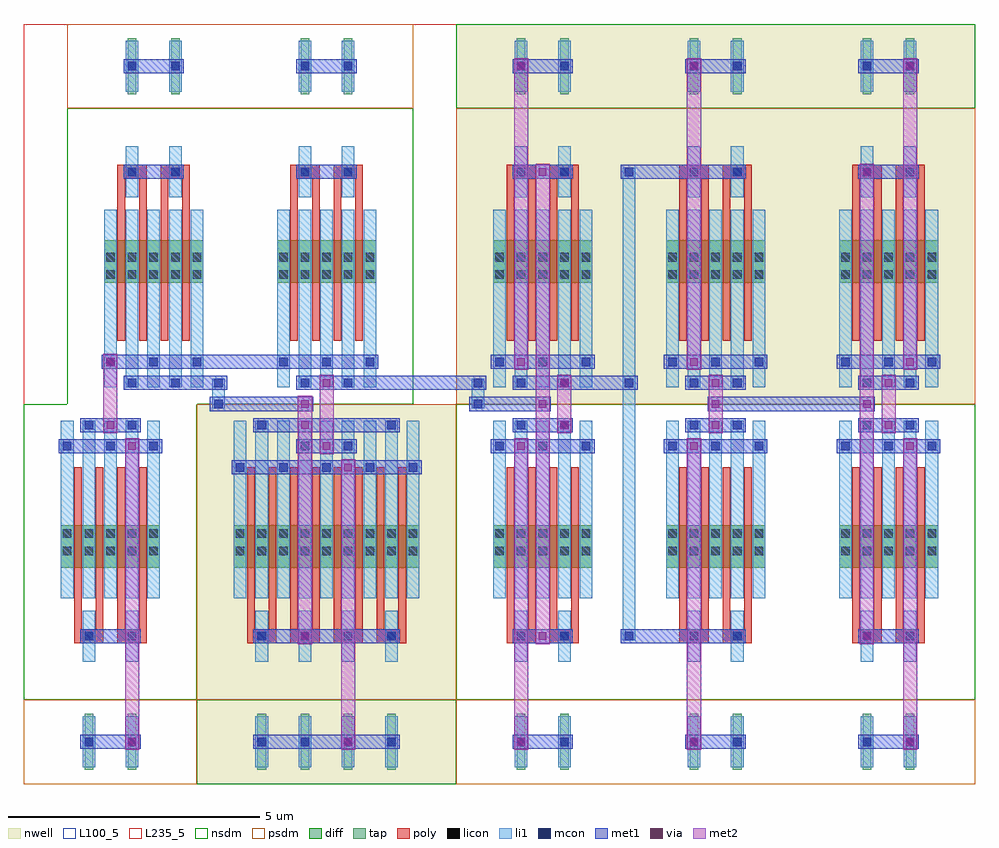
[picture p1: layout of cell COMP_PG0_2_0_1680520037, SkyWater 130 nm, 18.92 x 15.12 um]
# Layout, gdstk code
from math import pi, radians
import gdstk
lib = gdstk.Library(unit=1e-6, precision=1e-09)
def R(c, l, rs):  # rectangles x0, y0, x1, y1
    for r in rs: c.add(gdstk.rectangle(r[:2], r[2:], *l))
def A(c, l, x, y, w, h, nx, ny, dx, dy):  # array of equal rectangles
    R(c, l, [(x+i*dx, y+j*dy, x+i*dx+w, y+j*dy+h) for i in range(nx) for j in range(ny)])
def P(c, l, *ps):  # polygons
    for p in ps: c.add(gdstk.Polygon(p, *l))
nwell = (64, 20)
diff = (65, 20)
tap = (65, 44)
poly = (66, 20)
licon = (66, 44)
li1 = (67, 20)
mcon = (67, 44)
met1 = (68, 20)
via = (68, 44)
met2 = (69, 20)
nsdm = (93, 44)
psdm = (94, 20)
L100_5 = (100, 5)
L235_5 = (235, 5)

nmos_s_74334133_x2_y1_16 = lib.new_cell('NMOS_S_74334133_X2_Y1_1680520030_1680520031_1680520037')
R(nmos_s_74334133_x2_y1_16, diff, [(0.735,2.415,2.705,3.255)])
R(nmos_s_74334133_x2_y1_16, tap, [(1.205,6.16,1.375,7.28), (2.065,6.16,2.235,7.28)])
A(nmos_s_74334133_x2_y1_16, poly, 1, 1.26, 0.15, 3.36, 4, 1, 0.43, 0)
R(nmos_s_74334133_x2_y1_16, poly, [(1,4.485,1.58,4.755), (1.86,4.485,2.44,4.755)])
A(nmos_s_74334133_x2_y1_16, licon, 0.775, 2.495, 0.17, 0.17, 3, 2, 0.43, 0.34)
A(nmos_s_74334133_x2_y1_16, licon, 1.635, 2.495, 0.17, 0.17, 3, 2, 0.43, 0.34)
R(nmos_s_74334133_x2_y1_16, licon, [(1.205,4.535,1.375,4.705), (2.065,4.535,2.235,4.705), (1.205,6.635,1.375,6.805), (2.065,6.635,2.235,6.805)])
A(nmos_s_74334133_x2_y1_16, li1, 0.735, 0.335, 0.25, 3.53, 5, 1, 0.43, 0)
R(nmos_s_74334133_x2_y1_16, li1, [(1.165,4.115,1.415,5.125), (2.025,4.115,2.275,5.125), (1.165,6.215,1.415,7.225), (2.025,6.215,2.275,7.225)])
A(nmos_s_74334133_x2_y1_16, mcon, 0.775, 0.755, 0.17, 0.17, 3, 1, 0.86, 0)
R(nmos_s_74334133_x2_y1_16, mcon, [(1.205,0.335,1.375,0.505), (2.065,0.335,2.235,0.505), (1.205,4.535,1.375,4.705), (2.065,4.535,2.235,4.705), (1.205,6.635,1.375,6.805), (2.065,6.635,2.235,6.805)])
R(nmos_s_74334133_x2_y1_16, met1, [(1.12,0.28,2.32,0.56), (0.69,0.7,2.75,0.98), (1.12,4.48,2.32,4.76), (1.12,6.58,2.32,6.86)])
R(nmos_s_74334133_x2_y1_16, via, [(2.075,0.765,2.225,0.915), (2.075,6.645,2.225,6.795)])
R(nmos_s_74334133_x2_y1_16, met2, [(2.01,0.68,2.29,6.88)])
R(nmos_s_74334133_x2_y1_16, nsdm, [(0,0,3.44,5.88)])
R(nmos_s_74334133_x2_y1_16, psdm, [(0,5.88,3.44,7.56)])
R(nmos_s_74334133_x2_y1_16, L100_5, [(0,0,3.44,7.56)])

pmos_s_33331942_x2_y1_16 = lib.new_cell('PMOS_S_33331942_X2_Y1_1680520031_1680520031_1680520037')
R(pmos_s_33331942_x2_y1_16, nwell, [(0,0,3.44,7.56)])
R(pmos_s_33331942_x2_y1_16, diff, [(0.735,2.415,2.705,3.255)])
R(pmos_s_33331942_x2_y1_16, tap, [(1.205,6.16,1.375,7.28), (2.065,6.16,2.235,7.28)])
A(pmos_s_33331942_x2_y1_16, poly, 1, 1.26, 0.15, 3.36, 4, 1, 0.43, 0)
R(pmos_s_33331942_x2_y1_16, poly, [(1,4.485,1.58,4.755), (1.86,4.485,2.44,4.755)])
A(pmos_s_33331942_x2_y1_16, licon, 0.775, 2.495, 0.17, 0.17, 3, 2, 0.43, 0.34)
A(pmos_s_33331942_x2_y1_16, licon, 1.635, 2.495, 0.17, 0.17, 3, 2, 0.43, 0.34)
R(pmos_s_33331942_x2_y1_16, licon, [(1.205,4.535,1.375,4.705), (2.065,4.535,2.235,4.705), (1.205,6.635,1.375,6.805), (2.065,6.635,2.235,6.805)])
A(pmos_s_33331942_x2_y1_16, li1, 0.735, 0.335, 0.25, 3.53, 5, 1, 0.43, 0)
R(pmos_s_33331942_x2_y1_16, li1, [(1.165,4.115,1.415,5.125), (2.025,4.115,2.275,5.125), (1.165,6.215,1.415,7.225), (2.025,6.215,2.275,7.225)])
A(pmos_s_33331942_x2_y1_16, mcon, 0.775, 0.755, 0.17, 0.17, 3, 1, 0.86, 0)
R(pmos_s_33331942_x2_y1_16, mcon, [(1.205,0.335,1.375,0.505), (2.065,0.335,2.235,0.505), (1.205,4.535,1.375,4.705), (2.065,4.535,2.235,4.705), (1.205,6.635,1.375,6.805), (2.065,6.635,2.235,6.805)])
R(pmos_s_33331942_x2_y1_16, met1, [(1.12,0.28,2.32,0.56), (0.69,0.7,2.75,0.98), (1.12,4.48,2.32,4.76), (1.12,6.58,2.32,6.86)])
R(pmos_s_33331942_x2_y1_16, via, [(2.075,0.765,2.225,0.915), (2.075,6.645,2.225,6.795)])
R(pmos_s_33331942_x2_y1_16, met2, [(2.01,0.68,2.29,6.88)])
R(pmos_s_33331942_x2_y1_16, nsdm, [(0,5.88,3.44,7.56)])
R(pmos_s_33331942_x2_y1_16, psdm, [(0,0,3.44,5.88)])
R(pmos_s_33331942_x2_y1_16, L100_5, [(0,0,3.44,7.56)])

stage2_inv_90501218_pg0_ = lib.new_cell('STAGE2_INV_90501218_PG0_2_0_1680520031_1680520037')
R(stage2_inv_90501218_pg0_, li1, [(3.315,2.855,3.565,3.025), (3.315,2.855,3.565,3.025), (3.315,2.94,3.565,7.98), (3.315,7.895,3.565,8.065), (3.315,7.895,3.565,8.065), (3.315,7.895,3.565,8.065), (3.315,7.895,3.565,8.065), (3.315,7.895,3.565,8.065), (3.315,7.895,3.565,8.065), (3.315,7.98,3.565,12.18), (3.315,12.095,3.565,12.265), (3.315,12.095,3.565,12.265), (3.315,12.095,3.565,12.265), (3.315,12.095,3.565,12.265), (3.315,12.095,3.565,12.265), (3.315,12.095,3.565,12.265)])
R(stage2_inv_90501218_pg0_, mcon, [(3.355,2.855,3.525,3.025), (3.355,2.855,3.525,3.025), (3.355,7.895,3.525,8.065), (3.355,7.895,3.525,8.065), (3.355,7.895,3.525,8.065), (3.355,7.895,3.525,8.065), (3.355,7.895,3.525,8.065), (3.355,7.895,3.525,8.065), (3.355,12.095,3.525,12.265), (3.355,12.095,3.525,12.265), (3.355,12.095,3.525,12.265), (3.355,12.095,3.525,12.265), (3.355,12.095,3.525,12.265), (3.355,12.095,3.525,12.265)])
R(stage2_inv_90501218_pg0_, met1, [(2.15,2.8,3.44,3.08), (3.27,2.8,3.61,3.08), (3.27,2.8,3.61,3.08), (5,2.8,5.32,3.08), (5,2.8,5.32,3.08), (1.56,7,1.88,7.28), (1.56,7,1.88,7.28), (4.57,7,4.89,7.28), (4.57,7,4.89,7.28), (4.57,7,4.89,7.28), (4.57,7,4.89,7.28), (1.56,7.84,1.88,8.12), (1.56,7.84,1.88,8.12), (3.27,7.84,3.61,8.12), (3.27,7.84,3.61,8.12), (3.27,7.84,3.61,8.12), (3.27,7.84,3.61,8.12), (3.27,7.84,3.61,8.12), (3.27,7.84,3.61,8.12), (3.44,7.84,4.73,8.12), (4.57,7.84,4.89,8.12), (4.57,7.84,4.89,8.12), (4.57,7.84,4.89,8.12), (4.57,7.84,4.89,8.12), (2.15,12.04,3.44,12.32), (3.27,12.04,3.61,12.32), (3.27,12.04,3.61,12.32), (3.27,12.04,3.61,12.32), (3.27,12.04,3.61,12.32), (3.27,12.04,3.61,12.32), (3.27,12.04,3.61,12.32), (5,12.04,5.32,12.32), (5,12.04,5.32,12.32)])
P(stage2_inv_90501218_pg0_, met1, [(0,0),(0,0),(0,0),(0,0)],
  [(0,0),(0,0),(0,0),(0,0)],
  [(0,0),(0,0),(0,0),(0,0)],
  [(0,0),(0,0),(0,0),(0,0)],
  [(0,0),(0,0),(0,0),(0,0)],
  [(0,0),(0,0),(0,0),(0,0)],
  [(0,0),(0,0),(0,0),(0,0)],
  [(0,0),(0,0),(0,0),(0,0)])
R(stage2_inv_90501218_pg0_, via, [(5.085,2.865,5.235,3.015), (5.085,2.865,5.235,3.015), (1.645,7.065,1.795,7.215), (1.645,7.065,1.795,7.215), (4.655,7.065,4.805,7.215), (4.655,7.065,4.805,7.215), (4.655,7.065,4.805,7.215), (4.655,7.065,4.805,7.215), (1.645,7.905,1.795,8.055), (1.645,7.905,1.795,8.055), (4.655,7.905,4.805,8.055), (4.655,7.905,4.805,8.055), (4.655,7.905,4.805,8.055), (4.655,7.905,4.805,8.055), (5.085,12.105,5.235,12.255), (5.085,12.105,5.235,12.255)])
R(stage2_inv_90501218_pg0_, met2, [(5.02,2.78,5.3,3.1), (5.02,2.78,5.3,3.1), (5.02,2.94,5.3,12.18), (1.58,6.98,1.86,7.3), (1.58,6.98,1.86,7.3), (4.59,6.98,4.87,7.3), (4.59,6.98,4.87,7.3), (4.59,6.98,4.87,7.3), (4.59,6.98,4.87,7.3), (1.58,7.14,1.86,7.98), (4.59,7.14,4.87,7.98), (1.58,7.82,1.86,8.14), (1.58,7.82,1.86,8.14), (4.59,7.82,4.87,8.14), (4.59,7.82,4.87,8.14), (4.59,7.82,4.87,8.14), (4.59,7.82,4.87,8.14), (5.02,12.02,5.3,12.34), (5.02,12.02,5.3,12.34)])
P(stage2_inv_90501218_pg0_, met2, [(0,0),(0,0),(0,0),(0,0)],
  [(0,0),(0,0),(0,0),(0,0)],
  [(0,0),(0,0),(0,0),(0,0)],
  [(0,0),(0,0),(0,0),(0,0)])
R(stage2_inv_90501218_pg0_, L235_5, [(0,0,6.88,15.12)])
stage2_inv_90501218_pg0_.add(gdstk.Reference(nmos_s_74334133_x2_y1_16, (3.44,7.56), x_reflection=True))
stage2_inv_90501218_pg0_.add(gdstk.Reference(nmos_s_74334133_x2_y1_16, (0,7.56), x_reflection=True))
stage2_inv_90501218_pg0_.add(gdstk.Reference(pmos_s_33331942_x2_y1_16, (3.44,7.56)))
stage2_inv_90501218_pg0_.add(gdstk.Reference(pmos_s_33331942_x2_y1_16, (0,7.56)))

scm_pmos_23436893_x2_y1_ = lib.new_cell('SCM_PMOS_23436893_X2_Y1_1680520034_1680520037')
R(scm_pmos_23436893_x2_y1_, nwell, [(0,0,5.16,7.56)])
R(scm_pmos_23436893_x2_y1_, diff, [(0.735,2.415,4.425,3.255)])
A(scm_pmos_23436893_x2_y1_, tap, 1.205, 6.16, 0.17, 1.12, 4, 1, 0.86, 0)
A(scm_pmos_23436893_x2_y1_, poly, 1, 1.26, 0.15, 3.36, 8, 1, 0.43, 0)
A(scm_pmos_23436893_x2_y1_, poly, 1, 4.485, 0.58, 0.27, 4, 1, 0.86, 0)
A(scm_pmos_23436893_x2_y1_, licon, 0.775, 2.495, 0.17, 0.17, 3, 2, 0.43, 0.34)
A(scm_pmos_23436893_x2_y1_, licon, 1.635, 2.495, 0.17, 0.17, 3, 2, 0.43, 0.34)
A(scm_pmos_23436893_x2_y1_, licon, 2.495, 2.495, 0.17, 0.17, 3, 2, 0.43, 0.34)
A(scm_pmos_23436893_x2_y1_, licon, 3.355, 2.495, 0.17, 0.17, 3, 2, 0.43, 0.34)
A(scm_pmos_23436893_x2_y1_, licon, 1.205, 4.535, 0.17, 0.17, 4, 2, 0.86, 2.1)
A(scm_pmos_23436893_x2_y1_, li1, 0.735, 0.335, 0.25, 3.53, 9, 1, 0.43, 0)
A(scm_pmos_23436893_x2_y1_, li1, 1.165, 4.115, 0.25, 1.01, 4, 2, 0.86, 2.1)
A(scm_pmos_23436893_x2_y1_, mcon, 0.775, 1.175, 0.17, 0.17, 5, 1, 0.86, 0)
A(scm_pmos_23436893_x2_y1_, mcon, 1.205, 4.535, 0.17, 0.17, 4, 2, 0.86, 2.1)
R(scm_pmos_23436893_x2_y1_, mcon, [(1.205,0.335,1.375,0.505), (3.785,0.335,3.955,0.505), (2.065,0.755,2.235,0.925), (2.925,0.755,3.095,0.925)])
R(scm_pmos_23436893_x2_y1_, met1, [(1.12,0.28,4.04,0.56), (1.98,0.7,3.18,0.98), (0.69,1.12,4.47,1.4), (1.12,4.48,4.04,4.76), (1.12,6.58,4.04,6.86)])
R(scm_pmos_23436893_x2_y1_, via, [(2.075,0.345,2.225,0.495), (2.935,1.185,3.085,1.335), (2.075,4.545,2.225,4.695), (2.935,6.645,3.085,6.795)])
R(scm_pmos_23436893_x2_y1_, met2, [(2.01,0.26,2.29,4.78), (2.87,1.1,3.15,6.88)])
R(scm_pmos_23436893_x2_y1_, nsdm, [(0,5.88,5.16,7.56)])
R(scm_pmos_23436893_x2_y1_, psdm, [(0,0,5.16,5.88)])
R(scm_pmos_23436893_x2_y1_, L100_5, [(0,0,5.16,7.56)])

c_nmos_s_74334133_x2_y1_16 = lib.new_cell('NMOS_S_74334133_X2_Y1_1680520030_1680520030_1680520037')
R(c_nmos_s_74334133_x2_y1_16, diff, [(0.735,2.415,2.705,3.255)])
R(c_nmos_s_74334133_x2_y1_16, tap, [(1.205,6.16,1.375,7.28), (2.065,6.16,2.235,7.28)])
A(c_nmos_s_74334133_x2_y1_16, poly, 1, 1.26, 0.15, 3.36, 4, 1, 0.43, 0)
R(c_nmos_s_74334133_x2_y1_16, poly, [(1,4.485,1.58,4.755), (1.86,4.485,2.44,4.755)])
A(c_nmos_s_74334133_x2_y1_16, licon, 0.775, 2.495, 0.17, 0.17, 3, 2, 0.43, 0.34)
A(c_nmos_s_74334133_x2_y1_16, licon, 1.635, 2.495, 0.17, 0.17, 3, 2, 0.43, 0.34)
R(c_nmos_s_74334133_x2_y1_16, licon, [(1.205,4.535,1.375,4.705), (2.065,4.535,2.235,4.705), (1.205,6.635,1.375,6.805), (2.065,6.635,2.235,6.805)])
A(c_nmos_s_74334133_x2_y1_16, li1, 0.735, 0.335, 0.25, 3.53, 5, 1, 0.43, 0)
R(c_nmos_s_74334133_x2_y1_16, li1, [(1.165,4.115,1.415,5.125), (2.025,4.115,2.275,5.125), (1.165,6.215,1.415,7.225), (2.025,6.215,2.275,7.225)])
A(c_nmos_s_74334133_x2_y1_16, mcon, 0.775, 0.755, 0.17, 0.17, 3, 1, 0.86, 0)
R(c_nmos_s_74334133_x2_y1_16, mcon, [(1.205,0.335,1.375,0.505), (2.065,0.335,2.235,0.505), (1.205,4.535,1.375,4.705), (2.065,4.535,2.235,4.705), (1.205,6.635,1.375,6.805), (2.065,6.635,2.235,6.805)])
R(c_nmos_s_74334133_x2_y1_16, met1, [(1.12,0.28,2.32,0.56), (0.69,0.7,2.75,0.98), (1.12,4.48,2.32,4.76), (1.12,6.58,2.32,6.86)])
R(c_nmos_s_74334133_x2_y1_16, via, [(2.075,0.765,2.225,0.915), (2.075,6.645,2.225,6.795)])
R(c_nmos_s_74334133_x2_y1_16, met2, [(2.01,0.68,2.29,6.88)])
R(c_nmos_s_74334133_x2_y1_16, nsdm, [(0,0,3.44,5.88)])
R(c_nmos_s_74334133_x2_y1_16, psdm, [(0,5.88,3.44,7.56)])
R(c_nmos_s_74334133_x2_y1_16, L100_5, [(0,0,3.44,7.56)])

c_pmos_s_33331942_x2_y1_16 = lib.new_cell('PMOS_S_33331942_X2_Y1_1680520031_1680520030_1680520037')
R(c_pmos_s_33331942_x2_y1_16, nwell, [(0,0,3.44,7.56)])
R(c_pmos_s_33331942_x2_y1_16, diff, [(0.735,2.415,2.705,3.255)])
R(c_pmos_s_33331942_x2_y1_16, tap, [(1.205,6.16,1.375,7.28), (2.065,6.16,2.235,7.28)])
A(c_pmos_s_33331942_x2_y1_16, poly, 1, 1.26, 0.15, 3.36, 4, 1, 0.43, 0)
R(c_pmos_s_33331942_x2_y1_16, poly, [(1,4.485,1.58,4.755), (1.86,4.485,2.44,4.755)])
A(c_pmos_s_33331942_x2_y1_16, licon, 0.775, 2.495, 0.17, 0.17, 3, 2, 0.43, 0.34)
A(c_pmos_s_33331942_x2_y1_16, licon, 1.635, 2.495, 0.17, 0.17, 3, 2, 0.43, 0.34)
R(c_pmos_s_33331942_x2_y1_16, licon, [(1.205,4.535,1.375,4.705), (2.065,4.535,2.235,4.705), (1.205,6.635,1.375,6.805), (2.065,6.635,2.235,6.805)])
A(c_pmos_s_33331942_x2_y1_16, li1, 0.735, 0.335, 0.25, 3.53, 5, 1, 0.43, 0)
R(c_pmos_s_33331942_x2_y1_16, li1, [(1.165,4.115,1.415,5.125), (2.025,4.115,2.275,5.125), (1.165,6.215,1.415,7.225), (2.025,6.215,2.275,7.225)])
A(c_pmos_s_33331942_x2_y1_16, mcon, 0.775, 0.755, 0.17, 0.17, 3, 1, 0.86, 0)
R(c_pmos_s_33331942_x2_y1_16, mcon, [(1.205,0.335,1.375,0.505), (2.065,0.335,2.235,0.505), (1.205,4.535,1.375,4.705), (2.065,4.535,2.235,4.705), (1.205,6.635,1.375,6.805), (2.065,6.635,2.235,6.805)])
R(c_pmos_s_33331942_x2_y1_16, met1, [(1.12,0.28,2.32,0.56), (0.69,0.7,2.75,0.98), (1.12,4.48,2.32,4.76), (1.12,6.58,2.32,6.86)])
R(c_pmos_s_33331942_x2_y1_16, via, [(2.075,0.765,2.225,0.915), (2.075,6.645,2.225,6.795)])
R(c_pmos_s_33331942_x2_y1_16, met2, [(2.01,0.68,2.29,6.88)])
R(c_pmos_s_33331942_x2_y1_16, nsdm, [(0,5.88,3.44,7.56)])
R(c_pmos_s_33331942_x2_y1_16, psdm, [(0,0,3.44,5.88)])
R(c_pmos_s_33331942_x2_y1_16, L100_5, [(0,0,3.44,7.56)])

inv_46031338_pg0_2_0_168 = lib.new_cell('INV_46031338_PG0_2_0_1680520030_1680520037')
R(inv_46031338_pg0_2_0_168, met1, [(1.13,2.8,1.45,3.08), (1.13,2.8,1.45,3.08), (1.56,7,1.88,7.28), (1.56,7,1.88,7.28), (1.56,7.84,1.88,8.12), (1.56,7.84,1.88,8.12), (1.13,12.04,1.45,12.32), (1.13,12.04,1.45,12.32)])
P(inv_46031338_pg0_2_0_168, met1, [(0,0),(0,0),(0,0),(0,0)],
  [(0,0),(0,0),(0,0),(0,0)],
  [(0,0),(0,0),(0,0),(0,0)],
  [(0,0),(0,0),(0,0),(0,0)])
R(inv_46031338_pg0_2_0_168, via, [(1.215,2.865,1.365,3.015), (1.215,2.865,1.365,3.015), (1.645,7.065,1.795,7.215), (1.645,7.065,1.795,7.215), (1.645,7.905,1.795,8.055), (1.645,7.905,1.795,8.055), (1.215,12.105,1.365,12.255), (1.215,12.105,1.365,12.255)])
R(inv_46031338_pg0_2_0_168, met2, [(1.15,2.78,1.43,3.1), (1.15,2.78,1.43,3.1), (1.15,2.94,1.43,12.18), (1.58,6.98,1.86,7.3), (1.58,6.98,1.86,7.3), (1.58,7.14,1.86,7.98), (1.58,7.82,1.86,8.14), (1.58,7.82,1.86,8.14), (1.15,12.02,1.43,12.34), (1.15,12.02,1.43,12.34)])
P(inv_46031338_pg0_2_0_168, met2, [(0,0),(0,0),(0,0),(0,0)],
  [(0,0),(0,0),(0,0),(0,0)])
R(inv_46031338_pg0_2_0_168, L235_5, [(0,0,3.44,15.12)])
inv_46031338_pg0_2_0_168.add(gdstk.Reference(c_nmos_s_74334133_x2_y1_16, (0,7.56), x_reflection=True))
inv_46031338_pg0_2_0_168.add(gdstk.Reference(c_pmos_s_33331942_x2_y1_16, (0,7.56)))

c_nmos_s_74334133_x2_y1_16_ = lib.new_cell('NMOS_S_74334133_X2_Y1_1680520033_1680520037')
R(c_nmos_s_74334133_x2_y1_16_, diff, [(0.735,2.415,2.705,3.255)])
R(c_nmos_s_74334133_x2_y1_16_, tap, [(1.205,6.16,1.375,7.28), (2.065,6.16,2.235,7.28)])
A(c_nmos_s_74334133_x2_y1_16_, poly, 1, 1.26, 0.15, 3.36, 4, 1, 0.43, 0)
R(c_nmos_s_74334133_x2_y1_16_, poly, [(1,4.485,1.58,4.755), (1.86,4.485,2.44,4.755)])
A(c_nmos_s_74334133_x2_y1_16_, licon, 0.775, 2.495, 0.17, 0.17, 3, 2, 0.43, 0.34)
A(c_nmos_s_74334133_x2_y1_16_, licon, 1.635, 2.495, 0.17, 0.17, 3, 2, 0.43, 0.34)
R(c_nmos_s_74334133_x2_y1_16_, licon, [(1.205,4.535,1.375,4.705), (2.065,4.535,2.235,4.705), (1.205,6.635,1.375,6.805), (2.065,6.635,2.235,6.805)])
A(c_nmos_s_74334133_x2_y1_16_, li1, 0.735, 0.335, 0.25, 3.53, 5, 1, 0.43, 0)
R(c_nmos_s_74334133_x2_y1_16_, li1, [(1.165,4.115,1.415,5.125), (2.025,4.115,2.275,5.125), (1.165,6.215,1.415,7.225), (2.025,6.215,2.275,7.225)])
A(c_nmos_s_74334133_x2_y1_16_, mcon, 0.775, 0.755, 0.17, 0.17, 3, 1, 0.86, 0)
R(c_nmos_s_74334133_x2_y1_16_, mcon, [(1.205,0.335,1.375,0.505), (2.065,0.335,2.235,0.505), (1.205,4.535,1.375,4.705), (2.065,4.535,2.235,4.705), (1.205,6.635,1.375,6.805), (2.065,6.635,2.235,6.805)])
R(c_nmos_s_74334133_x2_y1_16_, met1, [(1.12,0.28,2.32,0.56), (0.69,0.7,2.75,0.98), (1.12,4.48,2.32,4.76), (1.12,6.58,2.32,6.86)])
R(c_nmos_s_74334133_x2_y1_16_, via, [(2.075,0.765,2.225,0.915), (2.075,6.645,2.225,6.795)])
R(c_nmos_s_74334133_x2_y1_16_, met2, [(2.01,0.68,2.29,6.88)])
R(c_nmos_s_74334133_x2_y1_16_, nsdm, [(0,0,3.44,5.88)])
R(c_nmos_s_74334133_x2_y1_16_, psdm, [(0,5.88,3.44,7.56)])
R(c_nmos_s_74334133_x2_y1_16_, L100_5, [(0,0,3.44,7.56)])

nmos_4t_77406006_x2_y1_1 = lib.new_cell('NMOS_4T_77406006_X2_Y1_1680520032_1680520037')
R(nmos_4t_77406006_x2_y1_1, diff, [(0.735,2.415,2.705,3.255)])
R(nmos_4t_77406006_x2_y1_1, tap, [(1.205,6.16,1.375,7.28), (2.065,6.16,2.235,7.28)])
A(nmos_4t_77406006_x2_y1_1, poly, 1, 1.26, 0.15, 3.36, 4, 1, 0.43, 0)
R(nmos_4t_77406006_x2_y1_1, poly, [(1,4.485,1.58,4.755), (1.86,4.485,2.44,4.755)])
A(nmos_4t_77406006_x2_y1_1, licon, 0.775, 2.495, 0.17, 0.17, 3, 2, 0.43, 0.34)
A(nmos_4t_77406006_x2_y1_1, licon, 1.635, 2.495, 0.17, 0.17, 3, 2, 0.43, 0.34)
R(nmos_4t_77406006_x2_y1_1, licon, [(1.205,4.535,1.375,4.705), (2.065,4.535,2.235,4.705), (1.205,6.635,1.375,6.805), (2.065,6.635,2.235,6.805)])
A(nmos_4t_77406006_x2_y1_1, li1, 0.735, 0.335, 0.25, 3.53, 5, 1, 0.43, 0)
R(nmos_4t_77406006_x2_y1_1, li1, [(1.165,4.115,1.415,5.125), (2.025,4.115,2.275,5.125), (1.165,6.215,1.415,7.225), (2.025,6.215,2.275,7.225)])
A(nmos_4t_77406006_x2_y1_1, mcon, 0.775, 0.755, 0.17, 0.17, 3, 1, 0.86, 0)
R(nmos_4t_77406006_x2_y1_1, mcon, [(1.205,0.335,1.375,0.505), (2.065,0.335,2.235,0.505), (1.205,4.535,1.375,4.705), (2.065,4.535,2.235,4.705), (1.205,6.635,1.375,6.805), (2.065,6.635,2.235,6.805)])
R(nmos_4t_77406006_x2_y1_1, met1, [(1.12,0.28,2.32,0.56), (0.69,0.7,2.75,0.98), (1.12,4.48,2.32,4.76), (1.12,6.58,2.32,6.86)])
R(nmos_4t_77406006_x2_y1_1, nsdm, [(0,0,3.44,5.88)])
R(nmos_4t_77406006_x2_y1_1, psdm, [(0,5.88,3.44,7.56)])
R(nmos_4t_77406006_x2_y1_1, L100_5, [(0,0,3.44,7.56)])

comp_pg0_2_0_1680520037 = lib.new_cell('COMP_PG0_2_0_1680520037')
R(comp_pg0_2_0_1680520037, li1, [(3.745,7.475,3.995,7.645), (3.745,7.475,3.995,7.645), (8.905,7.475,9.155,7.645), (8.905,7.475,9.155,7.645), (8.905,7.475,9.155,7.645), (8.905,7.475,9.155,7.645), (3.745,7.56,3.995,7.98), (8.905,7.56,9.155,7.98), (3.745,7.895,3.995,8.065), (3.745,7.895,3.995,8.065), (8.905,7.895,9.155,8.065), (8.905,7.895,9.155,8.065), (8.905,7.895,9.155,8.065), (8.905,7.895,9.155,8.065)])
R(comp_pg0_2_0_1680520037, mcon, [(3.785,7.475,3.955,7.645), (3.785,7.475,3.955,7.645), (8.945,7.475,9.115,7.645), (8.945,7.475,9.115,7.645), (8.945,7.475,9.115,7.645), (8.945,7.475,9.115,7.645), (3.785,7.895,3.955,8.065), (3.785,7.895,3.955,8.065), (8.945,7.895,9.115,8.065), (8.945,7.895,9.115,8.065), (8.945,7.895,9.115,8.065), (8.945,7.895,9.115,8.065)])
R(comp_pg0_2_0_1680520037, met1, [(5.86,6.58,6.18,6.86), (5.86,6.58,6.18,6.86), (1.56,7,1.88,7.28), (1.56,7,1.88,7.28), (3.7,7.42,4.04,7.7), (3.7,7.42,4.04,7.7), (3.87,7.42,5.59,7.7), (5.43,7.42,5.75,7.7), (5.43,7.42,5.75,7.7), (8.86,7.42,9.2,7.7), (8.86,7.42,9.2,7.7), (8.86,7.42,9.2,7.7), (8.86,7.42,9.2,7.7), (9.03,7.42,10.32,7.7), (10.16,7.42,10.48,7.7), (10.16,7.42,10.48,7.7), (10.16,7.42,10.48,7.7), (10.16,7.42,10.48,7.7), (13.6,7.42,13.92,7.7), (13.6,7.42,13.92,7.7), (13.76,7.42,16.77,7.7), (16.61,7.42,16.93,7.7), (16.61,7.42,16.93,7.7), (3.01,7.84,3.87,8.12), (3.7,7.84,4.04,8.12), (3.7,7.84,4.04,8.12), (5.86,7.84,6.18,8.12), (5.86,7.84,6.18,8.12), (6.45,7.84,9.03,8.12), (8.86,7.84,9.2,8.12), (8.86,7.84,9.2,8.12), (8.86,7.84,9.2,8.12), (8.86,7.84,9.2,8.12), (1.56,8.26,1.88,8.54), (1.56,8.26,1.88,8.54), (3.44,8.26,5.16,8.54)])
P(comp_pg0_2_0_1680520037, met1, [(0,0),(0,0),(0,0),(0,0)],
  [(0,0),(0,0),(0,0),(0,0)],
  [(0,0),(0,0),(0,0),(0,0)],
  [(0,0),(0,0),(0,0),(0,0)],
  [(0,0),(0,0),(0,0),(0,0)],
  [(0,0),(0,0),(0,0),(0,0)],
  [(0,0),(0,0),(0,0),(0,0)],
  [(0,0),(0,0),(0,0),(0,0)],
  [(0,0),(0,0),(0,0),(0,0)],
  [(0,0),(0,0),(0,0),(0,0)],
  [(0,0),(0,0),(0,0),(0,0)],
  [(0,0),(0,0),(0,0),(0,0)],
  [(0,0),(0,0),(0,0),(0,0)],
  [(0,0),(0,0),(0,0),(0,0)],
  [(0,0),(0,0),(0,0),(0,0)],
  [(0,0),(0,0),(0,0),(0,0)],
  [(0,0),(0,0),(0,0),(0,0)],
  [(0,0),(0,0),(0,0),(0,0)],
  [(0,0),(0,0),(0,0),(0,0)],
  [(0,0),(0,0),(0,0),(0,0)],
  [(0,0),(0,0),(0,0),(0,0)],
  [(0,0),(0,0),(0,0),(0,0)],
  [(0,0),(0,0),(0,0),(0,0)],
  [(0,0),(0,0),(0,0),(0,0)],
  [(0,0),(0,0),(0,0),(0,0)],
  [(0,0),(0,0),(0,0),(0,0)],
  [(0,0),(0,0),(0,0),(0,0)])
R(comp_pg0_2_0_1680520037, via, [(5.945,6.645,6.095,6.795), (5.945,6.645,6.095,6.795), (1.645,7.065,1.795,7.215), (1.645,7.065,1.795,7.215), (5.515,7.485,5.665,7.635), (5.515,7.485,5.665,7.635), (10.245,7.485,10.395,7.635), (10.245,7.485,10.395,7.635), (10.245,7.485,10.395,7.635), (10.245,7.485,10.395,7.635), (13.685,7.485,13.835,7.635), (13.685,7.485,13.835,7.635), (16.695,7.485,16.845,7.635), (16.695,7.485,16.845,7.635), (5.945,7.905,6.095,8.055), (5.945,7.905,6.095,8.055), (1.645,8.325,1.795,8.475), (1.645,8.325,1.795,8.475)])
R(comp_pg0_2_0_1680520037, met2, [(5.88,6.56,6.16,6.88), (5.88,6.56,6.16,6.88), (5.88,6.72,6.16,7.98), (1.58,6.98,1.86,7.3), (1.58,6.98,1.86,7.3), (1.58,7.14,1.86,8.4), (5.45,7.14,5.73,7.56), (5.45,7.4,5.73,7.72), (5.45,7.4,5.73,7.72), (10.18,7.4,10.46,7.72), (10.18,7.4,10.46,7.72), (10.18,7.4,10.46,7.72), (10.18,7.4,10.46,7.72), (13.62,7.4,13.9,7.72), (13.62,7.4,13.9,7.72), (16.63,7.4,16.91,7.72), (16.63,7.4,16.91,7.72), (5.88,7.82,6.16,8.14), (5.88,7.82,6.16,8.14), (1.58,8.24,1.86,8.56), (1.58,8.24,1.86,8.56)])
P(comp_pg0_2_0_1680520037, met2, [(0,0),(0,0),(0,0),(0,0)],
  [(0,0),(0,0),(0,0),(0,0)],
  [(0,0),(0,0),(0,0),(0,0)],
  [(0,0),(0,0),(0,0),(0,0)],
  [(0,0),(0,0),(0,0),(0,0)],
  [(0,0),(0,0),(0,0),(0,0)],
  [(0,0),(0,0),(0,0),(0,0)])
R(comp_pg0_2_0_1680520037, L235_5, [(0,0,18.92,15.12)])
comp_pg0_2_0_1680520037.add(gdstk.Reference(stage2_inv_90501218_pg0_, (15.48,0), rotation=pi, x_reflection=True))
comp_pg0_2_0_1680520037.add(gdstk.Reference(scm_pmos_23436893_x2_y1_, (3.44,7.56), x_reflection=True))
comp_pg0_2_0_1680520037.add(gdstk.Reference(inv_46031338_pg0_2_0_168, (15.48,0)))
comp_pg0_2_0_1680520037.add(gdstk.Reference(c_nmos_s_74334133_x2_y1_16_, (0,7.56), x_reflection=True))
comp_pg0_2_0_1680520037.add(gdstk.Reference(nmos_4t_77406006_x2_y1_1, (0.86,7.56)))
comp_pg0_2_0_1680520037.add(gdstk.Reference(nmos_4t_77406006_x2_y1_1, (4.3,7.56)))

lib.write_gds('COMP_PG0_2_0_1680520037.gds')
